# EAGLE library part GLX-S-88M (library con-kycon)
Mod. Jack, Right Angle, 8 posiotion, 8 contatcs RJ45 Source: GLX-S-88M.pdf

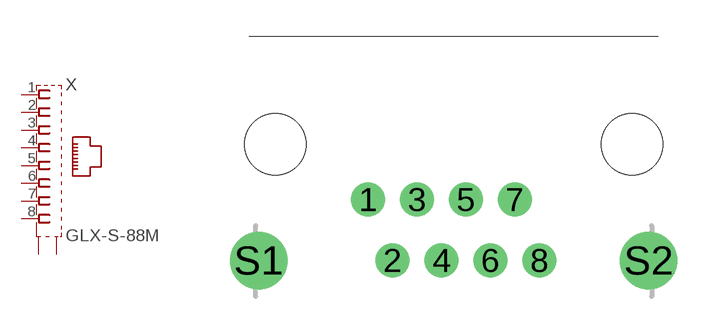
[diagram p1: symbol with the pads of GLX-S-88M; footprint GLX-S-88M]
Designator prefix X

## GLX-S-88M (OC_FARNELL: unknown; OC_NEWARK: unknown)  [GLX-S-88M]
1  1  pas
2  2  pas
3  3  pas
4  4  pas
5  5  pas
6  6  pas
7  7  pas
8  8  pas
S1  S1  pas
S2  S2  pas

## Footprint GLX-S-88M (pad centres in mm)
Mod. Jack, Right Angle, 8 posiotion, 8 contatcs RJ45 Source: GLX-S-88M.pdf
drill 0.9 pad 1.422: 1 -3.57,-2.3; 2 -2.55,-4.84; 3 -1.53,-2.3; 4 -0.51,-4.84; 5 0.51,-2.3; 6 1.53,-4.84; 7 2.55,-2.3; 8 3.57,-4.84
drill 1.6 pad 2.184: S1 -8.125,-4.84; S2 8.125,-4.84
hole 2.55 at -7.44,0
hole 2.55 at 7.44,0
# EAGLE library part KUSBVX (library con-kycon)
Vertical,Top Entry Universal Serial Bus Connector KUSBVX Series Source: KYCON Sibalco USB vertical socket KUSBV.pdf

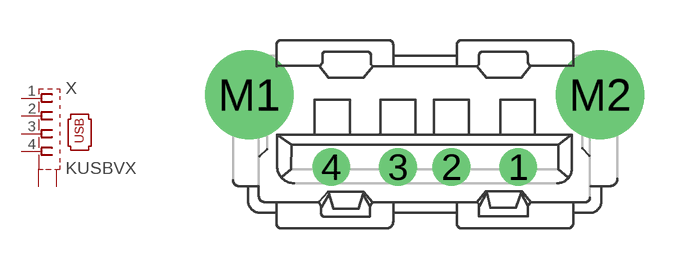
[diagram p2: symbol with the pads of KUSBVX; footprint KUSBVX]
Designator prefix X

## KUSBVX  [KUSBVX]
1  1  pas
2  2  pas
3  3  pas
4  4  pas
M1  S1  pas
M2  S2  pas

## Footprint KUSBVX (pad centres in mm)
Vertical,Top Entry Universal Serial Bus Connector KUSBVX Series Source: KYCON Sibalco USB vertical socket KUSBV.pdf
drill 0.9 pad 1.3: 1 3.5,0; 2 1,0; 3 -1,0; 4 -3.5,0
drill 2.3 pad 2.8: M1 -6.57,2.71; M2 6.57,2.71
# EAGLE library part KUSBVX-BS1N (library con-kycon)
USB B-type Receptacle Vertical, 4 Position, Through Hole Source: Sibalco Kycon KUSBVX-BS1N-xxx.pdf

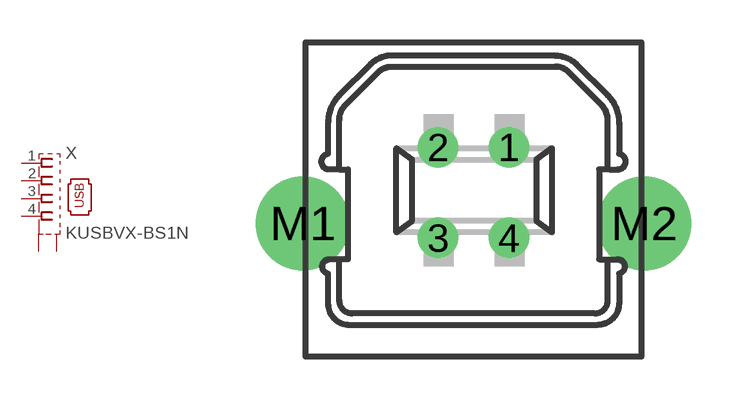
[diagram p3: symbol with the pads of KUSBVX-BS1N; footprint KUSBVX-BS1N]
Designator prefix X

## KUSBVX-BS1N  [KUSBVX-BS1N]
1  1  pas
2  2  pas
3  3  pas
4  4  pas
M1  S1  pas
M2  S2  pas

## Footprint KUSBVX-BS1N (pad centres in mm)
USB B-type Receptacle Vertical, 4 Position, Through Hole Source: Sibalco Kycon KUSBVX-BS1N-xxx.pdf
drill 0.9 pad 1.422: 1 1.25,2.7; 2 -1.25,2.7; 3 -1.25,-0.5; 4 1.25,-0.5
drill 2.3 pad 2.7: M1 -6.02,0; M2 6.02,0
